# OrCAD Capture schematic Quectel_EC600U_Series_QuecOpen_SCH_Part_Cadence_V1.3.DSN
size A1

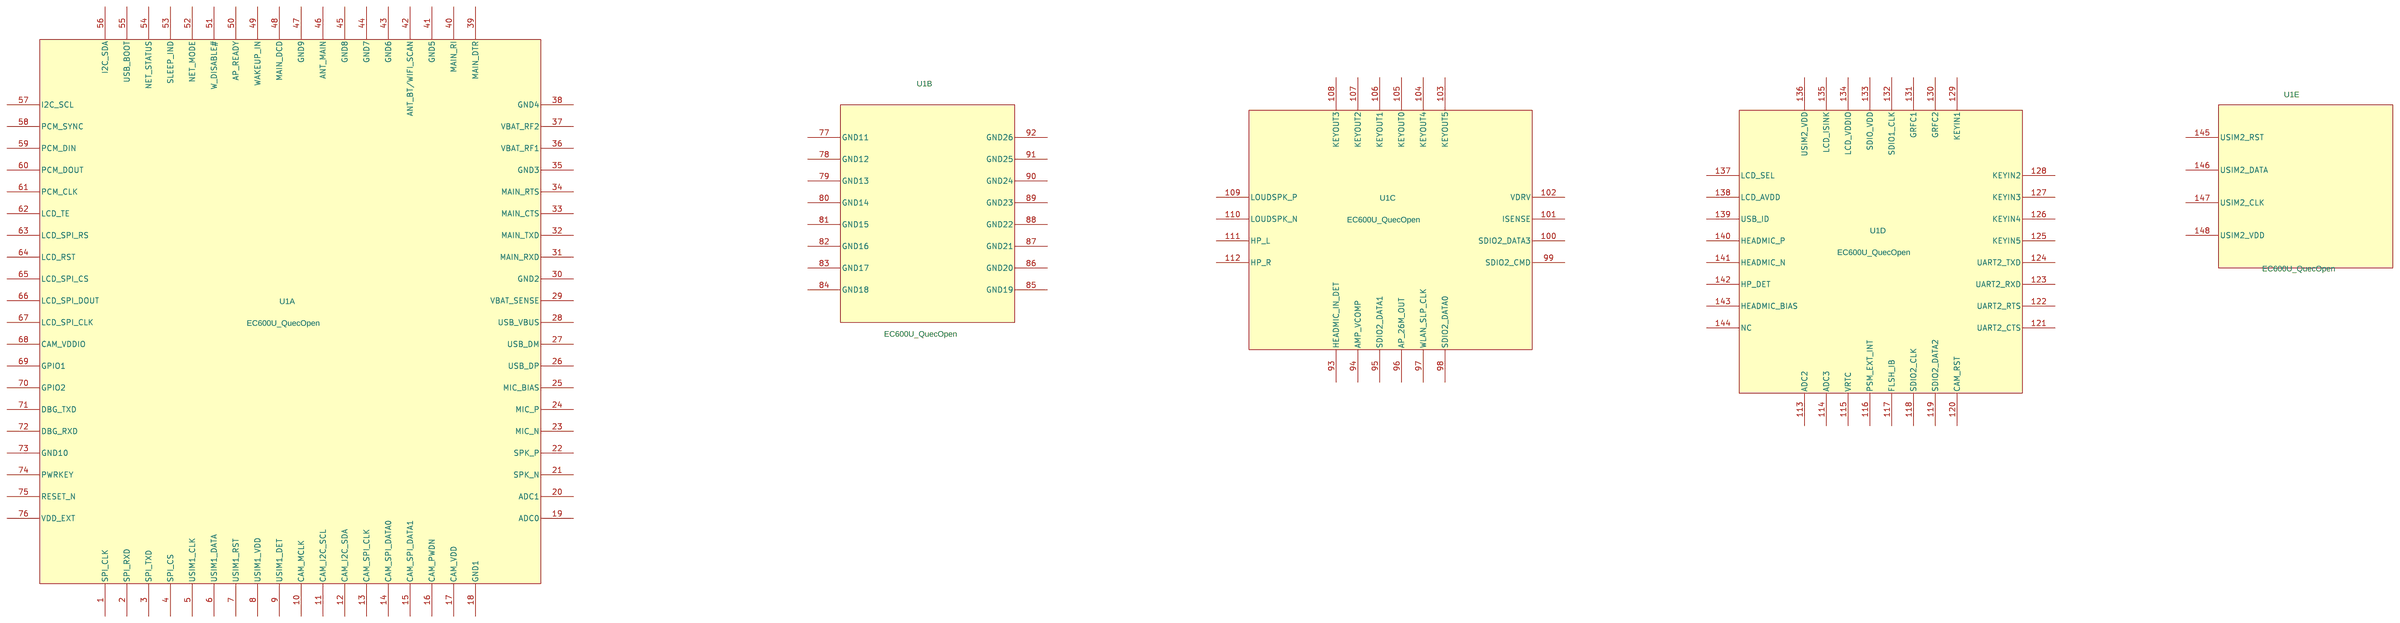
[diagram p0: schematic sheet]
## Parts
U1  EC600U_QuecOpen  [EC600U_QuecOpen]  (sections A,B,C,D,E)

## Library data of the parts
U1 = EC600U_QuecOpen

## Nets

Not connected (* = marked no-connect by the designer): U1 1(SPI_CLK) 2(SPI_RXD) 3(SPI_TXD) 4(SPI_CS) 5(USIM1_CLK) 6(USIM1_DATA) 7(USIM1_RST) 8(USIM1_VDD) 9(USIM1_DET) 10(CAM_MCLK) 11(CAM_I2C_SCL) 12(CAM_I2C_SDA) 13(CAM_SPI_CLK) 14(CAM_SPI_DATA0) 15(CAM_SPI_DATA1) 16(CAM_PWDN) 17(CAM_VDD) 18(GND1) 19(ADC0) 20(ADC1) 21(SPK_N) 22(SPK_P) 23(MIC_N) 24(MIC_P) 25(MIC_BIAS) 26(USB_DP) 27(USB_DM) 28(USB_VBUS) 29(VBAT_SENSE) 30(GND2) 31(MAIN_RXD) 32(MAIN_TXD) 33(MAIN_CTS) 34(MAIN_RTS) 35(GND3) 36(VBAT_RF1) 37(VBAT_RF2) 38(GND4) 39(MAIN_DTR) 40(MAIN_RI) 41(GND5) 42(ANT_BT/WIFI_SCAN) 43(GND6) 44(GND7) 45(GND8) 46(ANT_MAIN) 47(GND9) 48(MAIN_DCD) 49(WAKEUP_IN) 50(AP_READY) 51(W_DISABLE#) 52(NET_MODE) 53(SLEEP_IND) 54(NET_STATUS) 55(USB_BOOT) 56(I2C_SDA) 57(I2C_SCL) 58(PCM_SYNC) 59(PCM_DIN) 60(PCM_DOUT) 61(PCM_CLK) 62(LCD_TE) 63(LCD_SPI_RS) 64(LCD_RST) 65(LCD_SPI_CS) 66(LCD_SPI_DOUT) 67(LCD_SPI_CLK) 68(CAM_VDDIO) 69(GPIO1) 70(GPIO2) 71(DBG_TXD) 72(DBG_RXD) 73(GND10) 74(PWRKEY) 75(RESET_N) 76(VDD_EXT) 77(GND11) 78(GND12) 79(GND13) 80(GND14) 81(GND15) 82(GND16) 83(GND17) 84(GND18) 85(GND19) 86(GND20) 87(GND21) 88(GND22) 89(GND23) 90(GND24) 91(GND25) 92(GND26) 93(HEADMIC_IN_DET) 94(AMP_VCOMP) 95(SDIO2_DATA1) 96(AP_26M_OUT) 97(WLAN_SLP_CLK) 98(SDIO2_DATA0) 99(SDIO2_CMD) 100(SDIO2_DATA3) 101(ISENSE) 102(VDRV) 103(KEYOUT5) 104(KEYOUT4) 105(KEYOUT0) 106(KEYOUT1) 107(KEYOUT2) 108(KEYOUT3) 109(LOUDSPK_P) 110(LOUDSPK_N) 111(HP_L) 112(HP_R) 113(ADC2) 114(ADC3) 115(VRTC) 116(PSM_EXT_INT) 117(FLSH_IB) 118(SDIO2_CLK) 119(SDIO2_DATA2) 120(CAM_RST) 121(UART2_CTS) 122(UART2_RTS) 123(UART2_RXD) 124(UART2_TXD) 125(KEYIN5) 126(KEYIN4) 127(KEYIN3) 128(KEYIN2) 129(KEYIN1) 130(GRFC2) 131(GRFC1) 132(SDIO1_CLK) 133(SDIO_VDD) 134(LCD_VDDIO) 135(LCD_ISINK) 136(USIM2_VDD) 137(LCD_SEL) 138(LCD_AVDD) 139(USB_ID) 140(HEADMIC_P) 141(HEADMIC_N) 142(HP_DET) 143(HEADMIC_BIAS) 144(NC) 145(USIM2_RST) 146(USIM2_DATA) 147(USIM2_CLK) 148(USIM2_VDD)
